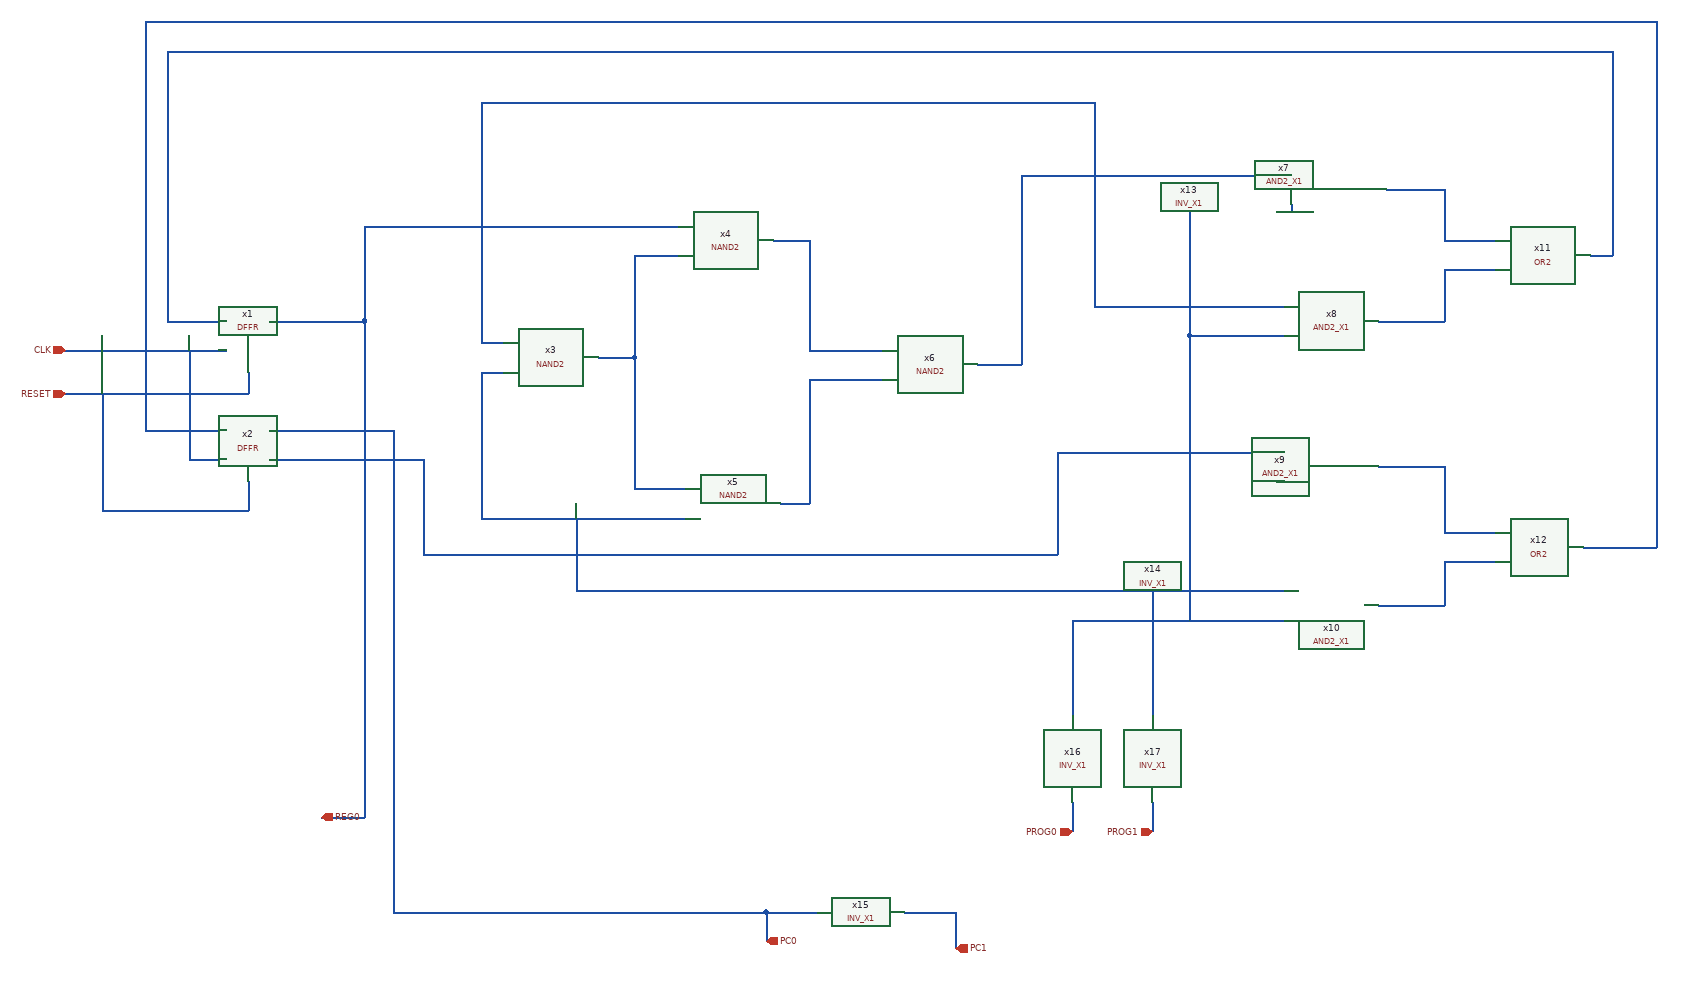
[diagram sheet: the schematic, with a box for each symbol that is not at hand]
v {xschem version=3.4.8RC file_version=1.3}
G {}
K {}
V {}
S {}
F {}
E {}
N -527030 -1425350 -526960 -1425350 {
lab=REG0}
N -526960 -1425480 -526960 -1425350 {
lab=REG0}
N -526960 -1425480 -526530 -1425480 {
lab=REG0}
N -526960 -1425350 -526960 -1424670 {
lab=REG0}
N -527020 -1424670 -526960 -1424670 {
lab=REG0}
N -526800 -1425320 -526770 -1425320 {
lab=REG0}
N -526800 -1425480 -526800 -1425320 {
lab=REG0}
N -526350 -1425310 -526250 -1425310 {
lab=#net1}
N -526350 -1425460 -526350 -1425310 {
lab=#net1}
N -526350 -1425270 -526350 -1425100 {
lab=#net2}
N -526350 -1425270 -526250 -1425270 {
lab=#net2}
N -526590 -1425440 -526590 -1425300 {
lab=#net3}
N -526590 -1425440 -526530 -1425440 {
lab=#net3}
N -526590 -1425300 -526590 -1425120 {
lab=#net3}
N -526590 -1425120 -526520 -1425120 {
lab=#net3}
N -526800 -1425280 -526770 -1425280 {
lab=#net4}
N -526800 -1425280 -526800 -1425080 {
lab=#net4}
N -526800 -1425080 -526520 -1425080 {
lab=#net4}
N -526800 -1425650 -526800 -1425480 {
lab=REG0}
N -526800 -1425650 -525960 -1425650 {
lab=REG0}
N -525960 -1425650 -525960 -1425370 {
lab=REG0}
N -525960 -1425370 -525700 -1425370 {
lab=REG0}
N -526060 -1425550 -525690 -1425550 {
lab=#net5}
N -526060 -1425550 -526060 -1425290 {
lab=#net5}
N -526670 -1424980 -525700 -1424980 {
lab=#net4}
N -526670 -1425080 -526670 -1424980 {
lab=#net4}
N -526010 -1425170 -525700 -1425170 {
lab=#net6}
N -526010 -1425170 -526010 -1425030 {
lab=#net6}
N -526880 -1425030 -526010 -1425030 {
lab=#net6}
N -526920 -1424640 -526920 -1424540 {
lab=PC0}
N -526410 -1424540 -526410 -1424500 {
lab=PC0}
N -526150 -1424540 -526150 -1424490 {
lab=PC1}
N -525480 -1425530 -525480 -1425460 {
lab=#net7}
N -525480 -1425460 -525410 -1425460 {
lab=#net7}
N -525480 -1425420 -525480 -1425350 {
lab=#net8}
N -525480 -1425420 -525410 -1425420 {
lab=#net8}
N -525480 -1425150 -525480 -1425060 {
lab=#net9}
N -525480 -1425060 -525410 -1425060 {
lab=#net9}
N -525480 -1425020 -525480 -1424960 {
lab=#net10}
N -525480 -1425020 -525410 -1425020 {
lab=#net10}
N -525990 -1424940 -525700 -1424940 {
lab=#net11}
N -525990 -1424690 -525990 -1424650 {
lab=PROG0}
N -525880 -1424690 -525880 -1424650 {
lab=PROG1}
N -525250 -1425720 -525250 -1425440 {
lab=#net12}
N -527230 -1425720 -525250 -1425720 {
lab=#net12}
N -527260 -1425760 -527260 -1425220 {
lab=#net13}
N -527260 -1425760 -525190 -1425760 {
lab=#net13}
N -525190 -1425760 -525190 -1425040 {
lab=#net13}
N -525830 -1425330 -525700 -1425330 {
lab=#net11}
N -527090 -1425350 -527030 -1425350 {lab=REG0}
N -527230 -1425350 -527150 -1425350 {lab=#net12}
N -527230 -1425720 -527230 -1425350 {lab=#net12}
N -527370 -1425310 -527150 -1425310 {lab=CLK}
N -527260 -1425200 -527150 -1425200 {lab=#net13}
N -527260 -1425220 -527260 -1425200 {lab=#net13}
N -527120 -1425280 -527120 -1425250 {lab=RESET}
N -527370 -1425250 -527120 -1425250 {lab=RESET}
N -527200 -1425310 -527200 -1425160 {lab=CLK}
N -527200 -1425160 -527150 -1425160 {lab=CLK}
N -527320 -1425250 -527320 -1425090 {lab=RESET}
N -527320 -1425090 -527120 -1425090 {lab=RESET}
N -527120 -1425130 -527120 -1425090 {lab=RESET}
N -527090 -1425160 -526880 -1425160 {lab=#net6}
N -527090 -1425200 -526920 -1425200 {lab=PC0}
N -526920 -1425200 -526920 -1424640 {lab=PC0}
N -526880 -1425160 -526880 -1425030 {lab=#net6}
N -525710 -1425130 -525700 -1425130 {lab=#net14}
N -525710 -1425500 -525690 -1425500 {lab=#net15}
N -525690 -1425510 -525690 -1425500 {lab=#net15}
N -525830 -1425500 -525830 -1425330 {lab=#net11}
N -525830 -1425330 -525830 -1425130 {lab=#net11}
N -525830 -1425130 -525830 -1424940 {lab=#net11}
N -525880 -1424980 -525880 -1424810 {lab=#net4}
N -525990 -1424940 -525990 -1424810 {lab=#net11}
N -526220 -1424540 -526150 -1424540 {lab=PC1}
N -526410 -1424540 -526340 -1424540 {lab=PC0}
N -526920 -1424540 -526410 -1424540 {lab=PC0}
N -526640 -1425300 -526590 -1425300 {lab=#net3}
N -526400 -1425460 -526350 -1425460 {lab=#net1}
N -526120 -1425290 -526060 -1425290 {lab=#net5}
N -526390 -1425100 -526350 -1425100 {lab=#net2}
N -525560 -1425530 -525480 -1425530 {lab=#net7}
N -525570 -1425350 -525480 -1425350 {lab=#net8}
N -525280 -1425440 -525250 -1425440 {lab=#net12}
N -525570 -1425150 -525480 -1425150 {lab=#net9}
N -525280 -1425040 -525190 -1425040 {lab=#net13}
N -525570 -1424960 -525480 -1424960 {lab=#net10}
N -525290 -1425040 -525280 -1425040 {lab=#net13}
C {devices/ipin.sym} -527370 -1425310 0 0 {name=p1 lab=CLK}
C {devices/ipin.sym} -527370 -1425250 0 0 {name=p2 lab=RESET}
C {devices/ipin.sym} -525880 -1424650 3 0 {name=p3 lab=PROG1}
C {devices/ipin.sym} -525990 -1424650 3 0 {name=p4 lab=PROG0}
C {devices/opin.sym} -527020 -1424670 2 0 {name=p18 lab=REG0}
C {devices/opin.sym} -526410 -1424500 1 0 {name=p7 lab=PC0}
C {devices/opin.sym} -526150 -1424490 1 0 {name=p8 lab=PC1}
C {IP62_5_stdcell/DFFR.sym} -527120 -1425320 0 0 {name=x1}
C {IP62_5_stdcell/DFFR.sym} -527120 -1425170 0 0 {name=x2}
C {IP62_5_stdcell/AND2_X1.sym} -525670 -1425530 0 0 {name=x7}
C {IP62_5_stdcell/AND2_X1.sym} -525680 -1425350 0 0 {name=x8}
C {IP62_5_stdcell/AND2_X1.sym} -525680 -1425150 0 0 {name=x9}
C {IP62_5_stdcell/AND2_X1.sym} -525680 -1424960 0 0 {name=x10}
C {IP62_5_stdcell/OR2.sym} -525390 -1425440 0 0 {name=x11}
C {IP62_5_stdcell/INV_X1.sym} -525810 -1425500 0 0 {name=x13}
C {IP62_5_stdcell/INV_X1.sym} -525810 -1425130 0 0 {name=x14}
C {IP62_5_stdcell/INV_X1.sym} -526320 -1424540 0 0 {name=x15}
C {IP62_5_stdcell/INV_X1.sym} -525990 -1424710 1 1 {name=x16}
C {IP62_5_stdcell/INV_X1.sym} -525880 -1424710 1 1 {name=x17}
C {IP62_5_stdcell/OR2.sym} -525400 -1425040 0 0 {name=x12}
C {IP62_5_stdcell/NAND2.sym} -526750 -1425300 0 0 {name=x3}
C {IP62_5_stdcell/NAND2.sym} -526510 -1425460 0 0 {name=x4}
C {IP62_5_stdcell/NAND2.sym} -526510 -1425100 0 0 {name=x5}
C {IP62_5_stdcell/NAND2.sym} -526240 -1425290 0 0 {name=x6}
